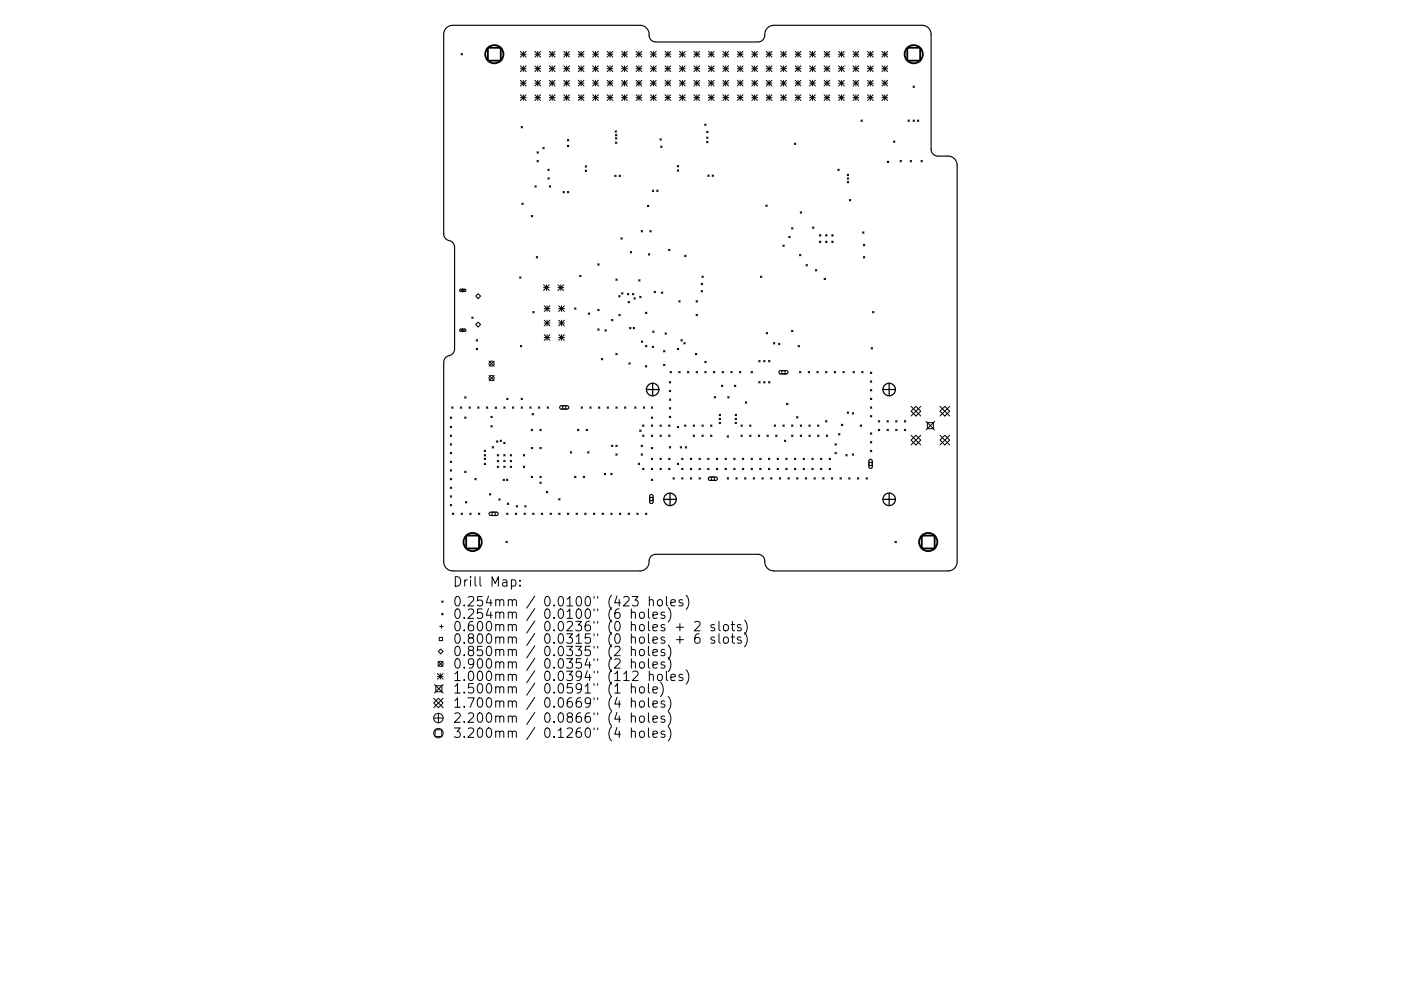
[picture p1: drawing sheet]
<svg xmlns="http://www.w3.org/2000/svg" width="297mm" height="210mm" viewBox="0 0 297 210" stroke-linecap="round" stroke-linejoin="round" font-family="sans-serif">
<defs><g id="words">
<g font-size="2.8">
<text x="96" y="124.5">Drill Map:</text>
<text x="96" y="128.7">0.254mm / 0.0100&quot; (423 holes)</text>
<text x="96" y="131.3">0.254mm / 0.0100&quot; (6 holes)</text>
<text x="96" y="133.9">0.600mm / 0.0236&quot; (0 holes + 2 slots)</text>
<text x="96" y="136.6">0.800mm / 0.0315&quot; (0 holes + 6 slots)</text>
<text x="96" y="139.2">0.850mm / 0.0335&quot; (2 holes)</text>
<text x="96" y="141.9">0.900mm / 0.0354&quot; (2 holes)</text>
<text x="96" y="144.5">1.000mm / 0.0394&quot; (112 holes)</text>
<text x="96" y="147.1">1.500mm / 0.0591&quot; (1 hole)</text>
<text x="96" y="150.1">1.700mm / 0.0669&quot; (4 holes)</text>
<text x="96" y="153.3">2.200mm / 0.0866&quot; (4 holes)</text>
<text x="96" y="156.5">3.200mm / 0.1260&quot; (4 holes)</text>
</g>
</g></defs>
<path d="M94.6 5.9l.7-.4 .7-.1h39.7a2.09 2.09 0 0 1 2 2.4l.4 .8 .8 .3h21.8a1.57 1.57 0 0 0 1.5-1.9 1.94 1.94 0 0 1 1.9-1.6h31.4a1.93 1.93 0 0 1 1.9 1.9v24.4a1.45 1.45 0 0 0 1.5 1.4h2.1a1.93 1.93 0 0 1 1.9 2v84.1a1.93 1.93 0 0 1-1.9 1.9h-36.9a2.09 2.09 0 0 1-2-2.4l-.5-.8-.8-.3h-21.7a1.57 1.57 0 0 0-1.5 1.9 1.94 1.94 0 0 1-1.9 1.6h-39.7a1.93 1.93 0 0 1-1.9-1.9v-42.3a1.73 1.73 0 0 1 1.6-1.6l.4-.5 .3-.7v-21.6a1.7 1.7 0 0 0-1.6-1.6l-.5-.5-.2-.8v-42.3l.1-.7zM97.5 61.4h1.1l.2 .3-.2 .1h-.9l-.2-.1zM97.5 69.9l1.1-.1 .2 .3-.2 .2h-.9l-.2-.2zM165.3 78.7l1.5-.1 .2 .2 .1 .2-.3 .3h-1.4l-.2-.2zM118.8 86.2l1.5-.1 .3 .4-.3 .3h-1.3l-.3-.2zM184.3 97.6l.4-.1 .2 .3v1.3l-.3 .3-.2-.1-.2-.2zM103.8 108.8l1.5-.1 .3 .4-.3 .3h-1.3l-.3-.3zM137.8 105l.4-.1 .3 .3v1.3l-.3 .3h-.3l-.2-.3zM150.3 101.3l1.5-.1 .2 .2 .1 .2-.3 .3h-1.3l-.3-.2z" fill="none" stroke="#000" stroke-width=".24"/>
<g fill="none" stroke="#000" stroke-width=".21">
<path d="M97.8 11.3l.3 .4M98.1 11.3l-.3 .4M110.3 10.9l1.2 1.2M110.3 11.5h1.2M110.3 14l1.2 1.2M110.3 14.6h1.2M110.3 17l1.2 1.3M110.3 17.6h1.2M110.9 10.9v1.2M110.9 14v1.2M110.9 17v1.3M111.5 10.9l-1.2 1.2"/>
<path d="M111.5 14l-1.2 1.2M111.5 17l-1.2 1.3M113.4 10.9l1.2 1.2M113.4 14l1.2 1.2M113.4 11.5h1.2M113.4 17l1.2 1.2M113.4 14.6h1.2M113.4 17.6h1.2M114 10.9v1.2M114 14v1.2M114 17v1.2M114.6 10.9l-1.2 1.2"/>
<path d="M114.6 14l-1.2 1.2M114.6 17l-1.2 1.2M116.5 14l1.2 1.2M116.5 17l1.2 1.2M116.5 11.5h1.2M116.5 14.6h1.2M116.5 17.6h1.2M116.5 10.9l1.2 1.2M117.1 10.9v1.2M117.1 14v1.2M117.1 17v1.2M117.7 14l-1.2 1.2"/>
<path d="M117.7 17l-1.2 1.2M117.7 10.9l-1.2 1.2M119.5 17l1.2 1.2M119.5 11.5h1.2M119.5 14.6h1.2M119.5 17.6h1.2M119.5 14l1.2 1.2M119.5 10.9l1.2 1.2M120.1 10.9v1.2M120.1 14v1.2M120.1 17v1.2M120.7 10.9l-1.2 1.2"/>
<path d="M120.7 14l-1.2 1.2M120.7 17l-1.2 1.2M122.6 11.5h1.2M122.6 14.6h1.2M122.6 17.6h1.2M122.6 17l1.2 1.2M122.6 14l1.2 1.2M122.6 10.9l1.2 1.2M123.2 10.9v1.2M123.2 14v1.2M123.2 17v1.2M123.8 10.9l-1.2 1.2"/>
<path d="M123.8 14l-1.2 1.2M123.8 17l-1.2 1.2M125.7 11.5h1.2M125.7 14.6h1.2M125.7 17.6h1.2M125.7 17l1.2 1.2M125.7 10.9l1.2 1.2M125.7 14l1.2 1.2M126.3 10.9v1.2M126.3 14v1.2M126.3 17v1.2M126.9 10.9l-1.2 1.2"/>
<path d="M126.9 14l-1.2 1.2M126.9 17l-1.2 1.2M128.7 11.5h1.2M128.7 14.6h1.2M128.7 17.6h1.2M128.7 14l1.2 1.2M128.7 17l1.2 1.2M128.7 10.9l1.2 1.2M129.3 10.9v1.2M129.3 14v1.2M129.3 17v1.2M129.9 10.9l-1.2 1.2"/>
<path d="M129.9 14l-1.2 1.2M129.9 17l-1.2 1.2M131.8 11.5h1.2M131.8 14.6h1.2M131.8 17.6h1.2M131.8 17l1.2 1.2M131.8 14l1.2 1.2M131.8 10.9l1.2 1.2M132.4 10.9v1.2M132.4 14v1.2M132.4 17v1.2M133 10.9l-1.2 1.2"/>
<path d="M133 14l-1.2 1.2M133 17l-1.2 1.2M134.9 11.5h1.2M134.9 14.6h1.2M134.9 17.6h1.2M134.9 17l1.2 1.2M134.9 14l1.2 1.2M134.9 10.9l1.2 1.2M135.5 10.9v1.2M135.5 14v1.2M135.5 17v1.2M136.1 17l-1.2 1.2"/>
<path d="M136.1 10.9l-1.2 1.2M136.1 14l-1.2 1.2M137.9 11.5h1.2M137.9 14.6h1.2M137.9 17.6h1.2M137.9 17l1.2 1.2M137.9 14l1.2 1.2M137.9 10.9l1.2 1.2M138.5 10.9v1.2M138.5 14v1.2M138.5 17v1.2M139.1 14l-1.2 1.2"/>
<path d="M139.1 17l-1.2 1.2M139.1 10.9l-1.2 1.2M141 11.5h1.2M141 14.6h1.2M141 17.6h1.2M141 17l1.2 1.2M141 14l1.2 1.2M141 10.9l1.2 1.2M141.6 10.9v1.2M141.6 14v1.2M141.6 17v1.2M142.2 10.9l-1.2 1.2"/>
<path d="M142.2 14l-1.2 1.2M142.2 17l-1.2 1.2M144.1 11.5h1.2M144.1 14.6h1.2M144.1 17.6h1.2M144.1 17l1.2 1.2M144.1 10.9l1.2 1.2M144.1 14l1.2 1.2M144.7 10.9v1.2M144.7 14v1.2M144.7 17v1.2M145.3 10.9l-1.2 1.2"/>
<path d="M145.3 14l-1.2 1.2M145.3 17l-1.2 1.2M147.1 11.5h1.2M147.1 14.6h1.2M147.1 17.6h1.2M147.1 17l1.2 1.2M147.1 10.9l1.2 1.2M147.1 14l1.2 1.2M147.7 10.9v1.2M147.7 14v1.2M147.7 17v1.2M148.3 10.9l-1.2 1.2"/>
<path d="M148.3 14l-1.2 1.2M148.3 17l-1.2 1.2M150.2 11.5h1.2M150.2 14.6h1.2M150.2 17.6h1.2M150.2 14l1.2 1.2M150.2 17l1.2 1.2M150.2 10.9l1.2 1.2M150.8 10.9v1.2M150.8 14v1.2M150.8 17v1.2M151.4 17l-1.2 1.2"/>
<path d="M151.4 10.9l-1.2 1.2M151.4 14l-1.2 1.2M153.3 11.5h1.2M153.3 14.6h1.2M153.3 17.6h1.2M153.3 17l1.2 1.2M153.3 14l1.2 1.2M153.3 10.9l1.2 1.2M153.9 10.9v1.2M153.9 14v1.2M153.9 17v1.2M154.5 10.9l-1.2 1.2"/>
<path d="M154.5 17l-1.2 1.2M154.5 14l-1.2 1.2M156.3 11.5h1.2M156.3 14.6h1.2M156.3 17.6h1.2M156.3 17l1.2 1.2M156.3 14l1.2 1.2M156.3 10.9l1.2 1.2M156.9 10.9v1.2M156.9 14v1.2M156.9 17v1.2M157.5 10.9l-1.2 1.2"/>
<path d="M157.5 14l-1.2 1.2M157.5 17l-1.2 1.2M159.4 11.5h1.2M159.4 14.6h1.2M159.4 17.6h1.2M159.4 17l1.2 1.2M159.4 14l1.2 1.2M159.4 10.9l1.2 1.2M160 10.9v1.2M160 14v1.2M160 17v1.2M160.6 10.9l-1.2 1.2"/>
<path d="M160.6 14l-1.2 1.2M160.6 17l-1.2 1.2M162.5 11.5h1.2M162.5 14.6h1.2M162.5 17.6h1.2M162.5 17l1.2 1.2M162.5 14l1.2 1.2M162.5 10.9l1.2 1.2M163.1 10.9v1.2M163.1 14v1.2M163.1 17v1.2M163.7 10.9l-1.2 1.2"/>
<path d="M163.7 14l-1.2 1.2M163.7 17l-1.2 1.2M165.5 11.5h1.2M165.5 14.6h1.2M165.5 17.6h1.2M165.5 17l1.2 1.2M165.5 10.9l1.2 1.2M165.5 14l1.2 1.2M166.1 10.9v1.2M166.1 14v1.2M166.1 17v1.2M166.7 10.9l-1.2 1.2"/>
<path d="M166.7 14l-1.2 1.2M166.7 17l-1.2 1.2M168.6 11.5h1.2M168.6 14.6h1.2M168.6 17.6h1.2M168.6 17l1.2 1.2M168.6 10.9l1.2 1.2M168.6 14l1.2 1.2M169.2 10.9v1.2M169.2 14v1.2M169.2 17v1.2M169.8 10.9l-1.2 1.2"/>
<path d="M169.8 14l-1.2 1.2M169.8 17l-1.2 1.2M171.7 11.5h1.2M171.7 14.6h1.2M171.7 17.6h1.2M171.7 14l1.2 1.2M171.7 17l1.2 1.2M171.7 10.9l1.2 1.2M172.3 10.9v1.2M172.3 14v1.2M172.3 17v1.2M172.9 10.9l-1.2 1.2"/>
<path d="M172.9 14l-1.2 1.2M172.9 17l-1.2 1.2M174.7 11.5h1.2M174.7 14.6h1.2M174.7 17.6h1.2M174.7 17l1.2 1.2M174.7 14l1.2 1.2M174.7 10.9l1.2 1.2M175.3 10.9v1.2M175.3 14v1.2M175.3 17v1.2M175.9 10.9l-1.2 1.2"/>
<path d="M175.9 14l-1.2 1.2M175.9 17l-1.2 1.2M177.8 11.5h1.2M177.8 14.6h1.2M177.8 17.6h1.2M177.8 17l1.2 1.2M177.8 14l1.2 1.2M177.8 10.9l1.2 1.2M178.4 10.9v1.2M178.4 14v1.2M178.4 17v1.2M179 10.9l-1.2 1.2"/>
<path d="M179 14l-1.2 1.2M179 17l-1.2 1.2M180.9 11.5h1.2M180.9 14.6h1.2M180.9 17.6h1.2M180.9 17l1.2 1.2M180.9 14l1.2 1.2M180.9 10.9l1.2 1.2M181.5 10.9v1.2M181.5 14v1.2M181.5 17v1.2M182.1 10.9l-1.2 1.2"/>
<path d="M182.1 14l-1.2 1.2M182.1 17l-1.2 1.2M183.9 11.5h1.2M183.9 14.6h1.2M183.9 17.6h1.2M183.9 17l1.2 1.2M183.9 14l1.2 1.2M183.9 10.9l1.2 1.2M184.5 10.9v1.2M184.5 14v1.2M184.5 17v1.2M185.1 17l-1.2 1.2"/>
<path d="M185.1 10.9l-1.2 1.2M185.1 14l-1.2 1.2M187 11.5h1.2M187 14.6h1.2M187 17.6h1.2M187 17l1.2 1.2M187 10.9l1.2 1.2M187 14l1.2 1.2M187.6 10.9v1.2M187.6 14v1.2M187.6 17v1.2M188.2 10.9l-1.2 1.2"/>
<path d="M188.2 14l-1.2 1.2M188.2 17l-1.2 1.2M193.6 18.2l.3 .4M193.9 18.2l-.3 .4M110.3 20.1l1.2 1.2M110.3 20.7h1.2M110.5 26.8l.3 .3M110.8 26.8l-.3 .3M110.9 20.1v1.2M111.5 20.1l-1.2 1.2M113.4 39.4l.3 .3M113.4 20.1l1.2 1.2"/>
<path d="M113.4 20.7h1.2M113.7 39.4l-.3 .3M113.9 32.2l.3 .3M113.9 34l.3 .3M114 20.1v1.2M114.2 32.2l-.3 .3M114.2 34l-.3 .3M114.6 20.1l-1.2 1.2M115.1 31.3l.3 .3M115.4 31.3l-.3 .3M116.2 35.9l.3 .3M116.2 37.7l.3 .3"/>
<path d="M116.5 35.9l-.3 .3M116.5 37.7l-.3 .3M116.5 39.4l.3 .3M116.5 20.1l1.2 1.2M116.5 20.7h1.2M116.8 39.4l-.3 .3M117.1 20.1v1.2M117.7 20.1l-1.2 1.2M119.5 20.1l1.2 1.2M119.5 20.7h1.2M120.1 20.1v1.2M120.3 29.6l.3 .3"/>
<path d="M120.3 30.8l.3 .3M120.6 29.6l-.3 .3M120.6 30.8l-.3 .3M120.7 20.1l-1.2 1.2M122.6 20.1l1.2 1.2M122.6 20.7h1.2M123.2 20.1v1.2M123.8 20.1l-1.2 1.2M124.1 35.2l.3 .3M124.1 36.1l.3 .3M124.4 35.2l-.3 .3M124.4 36.1l-.3 .3"/>
<path d="M125.7 20.7h1.2M125.7 20.1l1.2 1.2M126.3 20.1v1.2M126.9 20.1l-1.2 1.2M128.7 20.7h1.2M128.7 20.1l1.2 1.2M129.3 20.1v1.2M129.9 20.1l-1.2 1.2M130.3 37.2l.3 .3M130.4 27.8l.3 .3M130.5 28.5l.3 .3M130.5 29.2l.3 .3"/>
<path d="M130.5 30.1l.3 .3M130.6 37.2l-.3 .3M130.7 27.8l-.3 .3M130.8 28.5l-.3 .3M130.8 29.2l-.3 .3M130.8 30.1l-.3 .3M131.3 37.2l.3 .3M131.6 37.2l-.3 .3M131.8 20.7h1.2M131.8 20.1l1.2 1.2M132.4 20.1v1.2M133 20.1l-1.2 1.2"/>
<path d="M134.9 20.7h1.2M134.9 20.1l1.2 1.2M135.5 20.1v1.2M136.1 20.1l-1.2 1.2M137.9 20.7h1.2M137.9 20.1l1.2 1.2M138.5 20.1v1.2M139.1 20.1l-1.2 1.2M139.9 29.4l.3 .3M140.1 31l.3 .3M140.2 29.4l-.3 .3M140.4 31l-.3 .3"/>
<path d="M141 20.7h1.2M141 20.1l1.2 1.2M141.6 20.1v1.2M142.2 20.1l-1.2 1.2M143.6 35.1l.3 .3M143.6 36l.3 .3M143.9 35.1l-.3 .3M143.9 36l-.3 .3M144.1 20.7h1.2M144.1 20.1l1.2 1.2M144.7 20.1v1.2M145.3 20.1l-1.2 1.2"/>
<path d="M147.1 20.7h1.2M147.1 20.1l1.2 1.2M147.7 20.1v1.2M148.3 20.1l-1.2 1.2M149.4 26.3l.3 .3M149.7 26.3l-.3 .3M149.8 27.8l.3 .3M149.8 29.1l.3 .3M149.8 30l.3 .3M150.1 37.1l.3 .3M150.1 27.8l-.3 .3M150.1 29.1l-.3 .3"/>
<path d="M150.1 30l-.3 .3M150.2 20.7h1.2M150.2 20.1l1.2 1.2M150.4 37.1l-.3 .3M150.8 20.1v1.2M151 37.1l.3 .3M151.3 37.1l-.3 .3M151.4 20.1l-1.2 1.2M153.3 20.7h1.2M153.3 20.1l1.2 1.2M153.9 20.1v1.2M154.5 20.1l-1.2 1.2"/>
<path d="M156.3 20.7h1.2M156.3 20.1l1.2 1.2M156.9 20.1v1.2M157.5 20.1l-1.2 1.2M159.4 20.7h1.2M159.4 20.1l1.2 1.2M160 20.1v1.2M160.6 20.1l-1.2 1.2M162.5 20.7h1.2M162.5 20.1l1.2 1.2M163.1 20.1v1.2M163.7 20.1l-1.2 1.2"/>
<path d="M165.5 20.7h1.2M165.5 20.1l1.2 1.2M166.1 20.1v1.2M166.7 20.1l-1.2 1.2M168.4 30.4l.3 .3M168.6 20.7h1.2M168.6 20.1l1.2 1.2M168.7 30.4l-.3 .3M169.2 20.1v1.2M169.8 20.1l-1.2 1.2M171.7 20.7h1.2M171.7 20.1l1.2 1.2"/>
<path d="M172.3 20.1v1.2M172.9 20.1l-1.2 1.2M174.7 20.7h1.2M174.7 20.1l1.2 1.2M175.3 20.1v1.2M175.9 20.1l-1.2 1.2M177.6 35.9l.3 .3M177.8 20.7h1.2M177.8 20.1l1.2 1.2M177.9 35.9l-.3 .3M178.4 20.1v1.2M179 20.1l-1.2 1.2"/>
<path d="M179.6 37l.3 .3M179.6 37.7l.3 .3M179.6 38.5l.3 .3M179.9 38.5l-.3 .3M179.9 37.7l-.3 .3M179.9 37l-.3 .3M180.9 20.7h1.2M180.9 20.1l1.2 1.2M181.5 20.1v1.2M182.1 20.1l-1.2 1.2M182.5 25.5l.3 .3M182.8 25.5l-.3 .3"/>
<path d="M183.9 20.7h1.2M183.9 20.1l1.2 1.2M184.5 20.1v1.2M185.1 20.1l-1.2 1.2M187 20.7h1.2M187 20.1l1.2 1.2M187.6 20.1v1.2M188.1 34.2l.3 .3M188.2 20.1l-1.2 1.2M188.4 34.2l-.3 .3M189.4 29.9l.3 .3M189.7 29.9l-.3 .3"/>
<path d="M190.8 34l.3 .3M191.1 34l-.3 .3M192.5 25.5l.3 .3M192.8 25.5l-.3 .3M193 34l.3 .3M193.3 34l-.3 .3M193.6 25.5l.3 .3M193.9 25.5l-.3 .3M194.5 25.5l.3 .3M194.8 25.5l-.3 .3M195.3 34l.3 .3M195.6 34l-.3 .3"/>
<path d="M110.2 58.7l.3 .3M110.5 58.7l-.3 .3M110.6 43.1l.3 .3M110.9 43.1l-.3 .3M112.6 45.7l.3 .3M112.9 45.7l-.3 .3M113.7 54.4l.3 .3M114 54.4l-.3 .3M119.4 40.6l.3 .3M119.7 40.6l-.3 .3M120.3 40.6l.3 .3M120.6 40.6l-.3 .3"/>
<path d="M122.9 58.4l.3 .3M123.2 58.4l-.3 .3M126.7 56l.3 .3M127 56l-.3 .3M130.6 59.2l.3 .3M130.9 59.2l-.3 .3M131.6 50.4l.3 .4M131.9 50.4l-.3 .4M133.6 53.4l.3 .3M133.9 53.4l-.3 .3M135.4 59.3l.3 .3M135.7 59.3l-.3 .3"/>
<path d="M135.9 48.9l.3 .3M136.2 48.9l-.3 .3M137.3 43.5l.3 .3M137.5 53.8l.3 .3M137.6 43.5l-.3 .3M137.8 53.8l-.3 .3M137.8 48.9l.3 .3M138.1 48.9l-.3 .3M138.3 40.3l.3 .3M138.6 40.3l-.3 .3M139.2 40.3l.3 .3M139.5 40.3l-.3 .3"/>
<path d="M141.8 52.9l.3 .3M142.1 52.9l-.3 .3M145.2 54.2l.3 .3M145.5 54.2l-.3 .3M148.8 58.6l.3 .3M149.1 58.6l-.3 .3M161.2 58.6l.3 .3M161.5 58.6l-.3 .3M162.4 43.5l.3 .3M162.7 43.5l-.3 .3M166 52l.3 .3M166.3 52l-.3 .3"/>
<path d="M167.2 50.1l.3 .3M167.5 50.1l-.3 .3M167.8 48.3l.3 .3M168.1 48.3l-.3 .3M169.5 54l.3 .3M169.7 44.9l.3 .3M169.8 54l-.3 .3M170 44.9l-.3 .3M170.9 56.1l.3 .3M171.2 56.1l-.3 .3M172.3 48.1l.3 .4M172.6 48.1l-.3 .4"/>
<path d="M172.9 57.2l.3 .3M173.2 57.2l-.3 .3M174.7 59l.3 .3M175 59l-.3 .3M180.1 42.3l.3 .3M180.4 42.3l-.3 .3M182.9 49.2l.3 .3M183 51.9l.4 .3M183 54.4l.4 .3M183.2 49.2l-.3 .3M183.4 51.9l-.4 .3M183.4 54.4l-.4 .3"/>
<path d="M97.8 61.6h.7M97.8 70.1h.7M98.1 61.2v.8M98.1 69.7v.7M100 67.3l.3 .3M100.3 67.3l-.3 .3M100.9 68.9l.5-.6 .5 .6-.5 .5zM101 72.1l.3 .3M101 73.9l.3 .3M101.3 72.1l-.3 .3M101.3 73.9l-.3 .3M101.4 62.3l.5 .5-.5 .5-.5-.5z"/>
<path d="M103.7 76.6l1.1 1.1M103.7 79.7l1.1 1.1M104.8 76.6l-1.1 1.1M104.8 79.7l-1.1 1.1M110.3 73.3l.3 .3M110.6 73.3l-.3 .3M113 66.1l.3 .3M113.3 66.1l-.3 .3M115.2 60.4l1.2 1.2M115.2 61h1.2M115.4 64.9l1.2 1.2M115.4 65.5h1.2"/>
<path d="M115.4 67.9l1.2 1.2M115.4 68.5h1.2M115.4 71l1.2 1.2M115.4 71.6h1.2M115.8 60.4v1.2M116 64.9v1.2M116 67.9v1.2M116 71v1.2M116.4 60.4l-1.2 1.2M116.6 64.9l-1.2 1.2M116.6 67.9l-1.2 1.2M116.6 71l-1.2 1.2"/>
<path d="M118.3 60.4l1.2 1.2M118.3 61h1.2M118.5 64.9l1.2 1.2M118.5 67.9l1.2 1.2M118.5 65.5h1.2M118.5 71l1.2 1.2M118.5 68.5h1.2M118.5 71.6h1.2M118.9 60.4v1.2M119.1 64.9v1.2M119.1 67.9v1.2M119.1 71v1.2"/>
<path d="M119.5 60.4l-1.2 1.2M119.7 64.9l-1.2 1.2M119.7 67.9l-1.2 1.2M119.7 71l-1.2 1.2M121.8 65.3l.3 .3M122.1 65.3l-.3 .3M124.7 66.4l.3 .3M125 66.4l-.3 .3M126.7 65.6l.3 .3M126.7 69.8l.3 .3M127 65.6l-.3 .3M127 69.8l-.3 .3"/>
<path d="M127.5 76l.3 .4M127.8 76l-.3 .4M128.3 70l.3 .3M128.6 70l-.3 .3M129.6 67.8l.3 .3M129.9 67.8l-.3 .3M130.6 75l.3 .3M130.9 75l-.3 .3M131.2 62.7l.3 .3M131.2 66.7l.3 .3M131.5 62.7l-.3 .3M131.5 66.7l-.3 .3"/>
<path d="M131.8 62.1l.3 .3M132.1 62.1l-.3 .3M133 62.3l.3 .3M133.2 63.9l.3 .3M133.3 62.3l-.3 .3M133.3 77l.3 .3M133.5 63.9l-.3 .3M133.5 69.5l.3 .3M133.6 77l-.3 .3M133.8 69.5l-.3 .3M134.1 62.3l.3 .3M134.2 69.5l.3 .3"/>
<path d="M134.4 62.3l-.3 .3M134.4 63.2l.3 .3M134.5 69.5l-.3 .3M134.7 63.2l-.3 .3M135.6 62.9l.3 .3M135.9 62.9l-.3 .3M136 72.3l.3 .3M136.3 72.3l-.3 .3M136.8 77.6l.3 .3M136.8 66.2l.4 .3M136.8 73.3l.4 .3M137.1 77.6l-.3 .3"/>
<path d="M137.2 66.2l-.4 .3M137.2 73.3l-.4 .3M138.3 73.4l.3 .3M138.4 70.2l.3 .3M138.6 73.4l-.3 .3M138.7 70.2l-.3 .3M138.7 61.8l.3 .3M139 61.8l-.3 .3M140.2 61.9l.3 .4M140.5 61.9l-.3 .4M140.7 74.4l.3 .3M140.7 77.3l.3 .3"/>
<path d="M141 74.4l-.3 .3M141 77.3l-.3 .3M141 70.6l.3 .3M141.3 70.6l-.3 .3M142.1 78.8l.3 .3M142.4 78.8l-.3 .3M143.6 73.9l.3 .3M143.9 73.9l-.3 .3M143.9 63.8l.3 .3M143.9 78.8l.3 .3M144.2 78.8l-.3 .3M144.2 63.8l-.3 .3"/>
<path d="M144.4 72.1l.3 .3M144.7 72.1l-.3 .3M145 72.7l.3 .3M145.3 72.7l-.3 .3M145.7 78.8l.3 .3M146 78.8l-.3 .3M147.4 75l.3 .3M147.6 63.8l.3 .3M147.6 66.7l.3 .3M147.6 78.8l.3 .3M147.7 75l-.3 .3M147.9 66.7l-.3 .3"/>
<path d="M147.9 63.8l-.3 .3M147.9 78.8l-.3 .3M148.7 61.6l.3 .3M148.7 60.1l.3 .3M149 61.6l-.3 .3M149 60.1l-.3 .3M149.4 78.8l.3 .3M149.4 76.7l.3 .3M149.7 78.8l-.3 .3M149.7 76.7l-.3 .3M151.3 78.8l.3 .3M151.6 78.8l-.3 .3"/>
<path d="M153.1 78.8l.3 .3M153.4 78.8l-.3 .3M154.9 78.8l.3 .3M155.2 78.8l-.3 .3M156.8 78.8l.3 .3M157.1 78.8l-.3 .3M159.2 78.8l.3 .3M159.5 78.8l-.3 .3M160.9 76.5l.3 .3M161.2 76.5l-.3 .3M161.9 76.5l.3 .3M162.2 76.5l-.3 .3"/>
<path d="M162.5 70.5l.3 .3M162.8 70.5l-.3 .3M162.9 76.5l.4 .3M163.3 76.5l-.4 .3M164 72.7l.3 .3M164.3 72.7l-.3 .3M165.1 72.8l.3 .3M165.4 72.8l-.3 .3M165.8 78.6h.7v.7h-.7zM167.8 70.1l.3 .3M168.1 70.1l-.3 .3M169.2 73.3l.3 .3"/>
<path d="M169.5 73.3l-.3 .3M169.5 78.8l.3 .3M169.8 78.8l-.3 .3M171.3 78.8l.4 .3M171.7 78.8l-.4 .3M173.2 78.8l.3 .3M173.5 78.8l-.3 .3M175 78.8l.3 .3M175.3 78.8l-.3 .3M176.9 78.8l.3 .3M177.2 78.8l-.3 .3M178.7 78.8l.3 .3"/>
<path d="M179 78.8l-.3 .3M180.9 78.8l.3 .3M181.2 78.8l-.3 .3M182.7 78.8l.3 .3M183 78.8l-.3 .3M184.5 79l.3 .3M184.7 73.7l.3 .4M184.8 79l-.3 .3M185 66.1l.3 .3M185 73.7l-.3 .4M185.3 66.1l-.3 .3M95.5 88.5l.3 .3"/>
<path d="M95.5 90.5l.3 .3M95.5 92.3l.3 .3M95.5 94.1l.3 .3M95.5 96l.3 .3M95.5 97.8l.3 .3M95.5 99.7l.3 .3M95.8 88.5l-.3 .3M95.8 90.5l-.3 .3M95.8 92.3l-.3 .3M95.8 94.1l-.3 .3M95.8 96l-.3 .3M95.8 97.8l-.3 .3"/>
<path d="M95.8 99.7l-.3 .3M95.8 86.3l.3 .3M96.1 86.3l-.3 .3M97.6 86.3l.3 .3M97.9 86.3l-.3 .3M98.5 100l.3 .3M98.5 84.2l.3 .3M98.5 88.5l.3 .3M98.8 100l-.3 .3M98.8 84.2l-.3 .3M98.8 88.5l-.3 .3M99.4 86.3l.3 .3"/>
<path d="M99.7 86.3l-.3 .3M101.3 86.3l.3 .3M101.6 86.3l-.3 .3M102.7 95.5l.3 .3M102.7 96.4l.3 .3M102.7 98.3l.3 .3M102.7 97.2l.3 .3M103 95.5l-.3 .3M103 96.4l-.3 .3M103 98.3l-.3 .3M103 97.2l-.3 .3M103.1 86.3l.3 .3"/>
<path d="M103.4 86.3l-.3 .3M104.1 88.3l.3 .3M104.1 90.3l.3 .3M104.3 94.8l.4 .3M104.4 88.3l-.3 .3M104.4 90.3l-.3 .3M104.7 94.8l-.4 .3M105 86.4l.3 .3M105.3 93.5l.3 .3M105.3 86.4l-.3 .3M105.4 96.4l.3 .3M105.4 97.7l.3 .3"/>
<path d="M105.4 98.9l.3 .3M105.6 93.5l-.3 .3M105.7 96.4l-.3 .3M105.7 97.7l-.3 .3M105.7 98.9l-.3 .3M106 93.4l.3 .3M106.3 93.4l-.3 .3M106.8 93.8l.3 .3M106.8 96.4l.3 .3M106.8 97.7l.3 .3M106.8 86.3l.3 .3M106.8 98.9l.3 .3"/>
<path d="M107.1 93.8l-.3 .3M107.1 96.4l-.3 .3M107.1 97.7l-.3 .3M107.1 86.3l-.3 .3M107.1 98.9l-.3 .3M107.4 84.5l.3 .3M107.7 84.5l-.3 .3M108.2 96.4l.3 .3M108.2 97.7l.3 .3M108.2 98.9l.3 .3M108.5 96.4l-.3 .3M108.5 97.7l-.3 .3"/>
<path d="M108.5 98.9l-.3 .3M108.6 86.3l.3 .3M108.9 86.3l-.3 .3M110.5 84.5l.3 .3M110.5 86.3l.3 .3M110.8 84.5l-.3 .3M110.8 86.3l-.3 .3M110.9 96.4l.3 .3M110.9 98.9l.3 .3M111.2 96.4l-.3 .3M111.2 98.9l-.3 .3M112.3 86.3l.3 .3"/>
<path d="M112.6 91.1l.3 .3M112.6 94.9l.3 .3M112.6 86.3l-.3 .3M112.8 87.7l.3 .3M112.9 91.1l-.3 .3M112.9 94.9l-.3 .3M113.1 87.7l-.3 .3M114.2 86.3l.3 .3M114.5 91.1l.3 .3M114.5 94.9l.3 .3M114.5 86.3l-.3 .3M114.8 91.1l-.3 .3"/>
<path d="M114.8 94.9l-.3 .3M116 86.3l.3 .3M116.3 86.3l-.3 .3M119.3 86.1h.7v.7h-.7zM120.9 95.8l.3 .3M121.2 95.8l-.3 .3M122.4 91.1l.3 .3M122.7 91.1l-.3 .3M123.2 86.3l.3 .3M123.5 86.3l-.3 .3M124.3 91.1l.3 .3M124.6 91.1l-.3 .3"/>
<path d="M124.6 95.8l.3 .3M124.9 95.8l-.3 .3M125 86.3l.3 .3M125.3 86.3l-.3 .3M126.9 86.3l.3 .3M127.2 86.3l-.3 .3M128.7 86.3l.3 .3M129 86.3l-.3 .3M129.6 94.4l.3 .4M129.9 94.4l-.3 .4M130.6 86.3l.3 .3M130.6 94.4l.3 .4"/>
<path d="M130.6 96.3l.3 .3M130.9 86.3l-.3 .3M130.9 94.4l-.3 .4M130.9 96.3l-.3 .3M132.4 86.3l.3 .3M132.7 86.3l-.3 .3M134.5 86.3l.4 .3M134.9 86.3l-.4 .3M135.3 98.3l.3 .3M135.6 98.3l-.3 .3M135.6 91.2l.3 .3M135.9 91.2l-.3 .3"/>
<path d="M135.9 94.4l.3 .4M135.9 96.3l.3 .3M136.2 99.4l.3 .3M136.2 90.2l.3 .3M136.2 94.4l-.3 .4M136.2 96.3l-.3 .3M136.2 92.3l.3 .3M136.4 86.3l.3 .3M136.5 92.3l-.3 .3M136.5 90.2l-.3 .3M136.5 99.4l-.3 .3M136.7 86.3l-.3 .3"/>
<path d="M138.1 86.3l.3 .3M138.1 88.5l.3 .3M138.1 90.2l.3 .3M138.1 92.3l.3 .3M138.1 94.9l.3 .3M138.1 97.2l.3 .3M138.1 99.4l.3 .3M138.4 92.3l-.3 .3M138.4 86.3l-.3 .3M138.4 88.5l-.3 .3M138.4 90.2l-.3 .3M138.4 94.9l-.3 .3"/>
<path d="M138.4 97.2l-.3 .3M138.4 99.4l-.3 .3M139.9 99.4l.3 .3M139.9 90.2l.3 .3M139.9 92.3l.3 .3M139.9 97.2l.3 .3M140.2 92.3l-.3 .3M140.2 90.2l-.3 .3M140.2 97.2l-.3 .3M140.2 99.4l-.3 .3M141.8 90.2l.3 .3M141.8 92.3l.3 .3"/>
<path d="M141.8 97.2l.3 .3M141.8 99.4l.3 .3M141.9 81l.3 .3M141.9 82.8l.3 .3M141.9 84.6l.3 .3M141.9 86.5l.3 .3M141.9 88.3l.3 .3M141.9 94.8l.3 .3M142.1 90.2l-.3 .3M142.1 92.3l-.3 .3M142.1 97.2l-.3 .3M142.1 99.4l-.3 .3"/>
<path d="M142.2 81l-.3 .3M142.2 82.8l-.3 .3M142.2 84.6l-.3 .3M142.2 86.5l-.3 .3M142.2 88.3l-.3 .3M142.2 94.8l-.3 .3M143.6 90.5l.3 .3M143.6 98.3l.3 .3M143.9 90.5l-.3 .3M143.9 98.3l-.3 .3M144.2 94.8l.3 .3M144.5 94.8l-.3 .3"/>
<path d="M144.5 97.2l.3 .3M144.5 99.4l.3 .3M144.8 97.2l-.3 .3M144.8 99.4l-.3 .3M145.1 90.2l.3 .3M145.3 94.8l.3 .3M145.4 90.2l-.3 .3M145.6 94.8l-.3 .3M146.4 99.4l.3 .3M146.4 97.2l.3 .3M146.7 99.4l-.3 .3M146.7 97.2l-.3 .3"/>
<path d="M147 90.2l.3 .3M147 92.3l.3 .3M147.3 90.2l-.3 .3M147.3 92.3l-.3 .3M148.2 97.2l.3 .3M148.2 99.4l.3 .3M148.5 97.2l-.3 .3M148.5 99.4l-.3 .3M148.8 90.2l.3 .3M148.8 92.3l.3 .3M149.1 90.2l-.3 .3M149.1 92.3l-.3 .3"/>
<path d="M150 97.2l.3 .3M150 99.4l.3 .3M150.3 97.2l-.3 .3M150.3 99.4l-.3 .3M150.6 92.3l.4 .3M150.6 90.2l.4 .3M151 90.2l-.4 .3M151 92.3l-.4 .3M151.4 84.1l.3 .3M151.7 84.1l-.3 .3M151.9 97.2l.3 .3M151.9 99.4l.3 .3"/>
<path d="M152.2 97.2l-.3 .3M152.2 99.4l-.3 .3M152.5 87.9l.3 .3M152.5 88.7l.3 .3M152.5 89.6l.3 .3M152.8 89.6l-.3 .3M152.8 87.9l-.3 .3M152.8 88.7l-.3 .3M152.9 81.7l.4 .3M153.3 81.7l-.4 .3M153.7 97.2l.3 .3M153.7 99.4l.3 .3"/>
<path d="M154 97.2l-.3 .3M154 99.4l-.3 .3M154.2 92.5l.3 .3M154.3 84.1l.3 .3M154.5 92.5l-.3 .3M154.6 84.1l-.3 .3M155.6 97.2l.3 .3M155.6 99.4l.3 .3M155.7 81.7l.3 .3M155.9 89.6l.3 .3M155.9 97.2l-.3 .3M155.9 99.4l-.3 .3"/>
<path d="M155.9 87.9l.3 .3M155.9 88.7l.3 .3M156 81.7l-.3 .3M156.2 89.6l-.3 .3M156.2 87.9l-.3 .3M156.2 88.7l-.3 .3M157.1 92.3l.3 .3M157.1 90.2l.3 .3M157.4 90.2l-.3 .3M157.4 92.3l-.3 .3M157.4 97.2l.3 .3M157.4 99.4l.3 .3"/>
<path d="M157.7 97.2l-.3 .3M157.7 99.4l-.3 .3M158 85.2l.3 .4M158.3 85.2l-.3 .4M158.9 90.2l.3 .3M158.9 92.3l.3 .3M159.2 90.2l-.3 .3M159.2 92.3l-.3 .3M159.2 97.2l.3 .3M159.2 99.4l.3 .3M159.5 97.2l-.3 .3M159.5 99.4l-.3 .3"/>
<path d="M160.8 92.3l.3 .3M160.9 81l.3 .3M161.1 92.3l-.3 .3M161.1 97.2l.3 .3M161.1 99.4l.3 .3M161.2 81l-.3 .3M161.4 97.2l-.3 .3M161.4 99.4l-.3 .3M161.9 81l.3 .3M162.2 81l-.3 .3M162.6 92.3l.3 .3M162.9 92.3l-.3 .3"/>
<path d="M162.9 97.2l.3 .3M162.9 99.4l.3 .3M162.9 81l.4 .3M163.2 97.2l-.3 .3M163.2 99.4l-.3 .3M163.3 81l-.4 .3M164.1 90.2l.3 .3M164.4 90.2l-.3 .3M164.4 92.3l.4 .3M164.8 92.3l-.4 .3M164.8 97.2l.3 .3M164.8 99.4l.3 .3"/>
<path d="M165.1 97.2l-.3 .3M165.1 99.4l-.3 .3M166 90.2l.3 .3M166.3 90.2l-.3 .3M166.3 93.4l.3 .3M166.6 93.4l-.3 .3M166.6 97.2l.3 .3M166.6 99.4l.3 .3M166.7 85.6l.4 .3M166.9 97.2l-.3 .3M166.9 99.4l-.3 .3M167.1 85.6l-.4 .3"/>
<path d="M167.8 90.2l.3 .3M167.8 92.3l.3 .3M168.1 92.3l-.3 .3M168.1 90.2l-.3 .3M168.4 97.2l.3 .3M168.4 99.4l.3 .3M168.7 97.2l-.3 .3M168.7 99.4l-.3 .3M168.9 88.4l.3 .3M169.2 88.4l-.3 .3M169.7 90.2l.3 .3M169.7 92.3l.3 .3"/>
<path d="M170 92.3l-.3 .3M170 90.2l-.3 .3M170.3 99.4l.3 .3M170.3 97.2l.3 .3M170.6 97.2l-.3 .3M170.6 99.4l-.3 .3M171.5 90.2l.3 .3M171.5 92.3l.3 .3M171.8 90.2l-.3 .3M171.8 92.3l-.3 .3M172.1 99.4l.3 .3M172.1 97.2l.3 .3"/>
<path d="M172.4 97.2l-.3 .3M172.4 99.4l-.3 .3M173.3 90.2l.3 .3M173.3 92.3l.3 .3M173.6 92.3l-.3 .3M173.6 90.2l-.3 .3M174 97.2l.3 .3M174 99.4l.3 .3M174.3 97.2l-.3 .3M174.3 99.4l-.3 .3M175 89.2l.3 .3M175.2 92.3l.3 .3"/>
<path d="M175.3 89.2l-.3 .3M175.5 92.3l-.3 .3M175.8 97.2l.3 .3M175.8 99.4l.3 .3M176.1 97.2l-.3 .3M176.1 99.4l-.3 .3M177 96l.3 .3M177 94.1l.3 .3M177.3 94.1l-.3 .3M177.3 96l-.3 .3M177.8 92l.3 .3M178.1 92l-.3 .3"/>
<path d="M178.4 90l.3 .3M178.7 90l-.3 .3M179.3 96.4l.3 .3M179.6 96.4l-.3 .3M179.6 87.4l.3 .3M179.9 87.4l-.3 .3M180.7 96.3l.3 .3M180.7 87.5l.3 .4M181 87.5l-.3 .4M181 96.3l-.3 .3M182.4 90.2l.3 .3M182.7 90.2l-.3 .3"/>
<path d="M184.2 98.1h.7v.7h-.7zM184.5 93.7l.3 .3M184.5 95.5l.3 .3M184.5 80.8l.3 .3M184.5 82.6l.3 .3M184.5 84.5l.3 .3M184.5 86.3l.3 .3M184.5 88.2l.3 .3M184.5 91.8l.3 .3M184.8 80.8l-.3 .3M184.8 82.6l-.3 .3M184.8 84.5l-.3 .3"/>
<path d="M184.8 86.3l-.3 .3M184.8 88.2l-.3 .3M184.8 91.8l-.3 .3M184.8 93.7l-.3 .3M184.8 95.5l-.3 .3M186.2 89.2l.3 .3M186.2 91.1l.3 .3M186.5 89.2l-.3 .3M186.5 91.1l-.3 .3M188.1 91.1l.3 .3M188.1 89.2l.3 .3M188.4 89.2l-.3 .3"/>
<path d="M188.4 91.1l-.3 .3M189.9 91.1l.3 .3M189.9 89.2l.3 .3M190.2 89.2l-.3 .3M190.2 91.1l-.3 .3M191.7 91.1l.3 .3M191.7 89.2l.3 .3M192 89.2l-.3 .3M192 91.1l-.3 .3M193.2 86.2l2 2.1M193.2 92.3l2 2.1M194.2 86.2l1 1-1 1.1-1-1.1z"/>
<path d="M194.2 92.3l1 1.1-1 1-1-1zM195.2 92.3l-2 2.1M195.2 86.2l-2 2.1M196.4 89.4l1.8 1.8M196.6 89.7h1.3v1.2h-1.3zM198.2 89.4l-1.8 1.8M199.3 87.2l1-1 1 1-1 1.1zM199.3 93.4l1-1.1 1 1.1-1 1zM199.3 86.2l2 2.1M199.3 92.3l2 2.1M201.3 86.2l-2 2.1M201.3 92.3l-2 2.1"/>
<path d="M95.5 101.5l.3 .3M95.5 103.3l.3 .3M95.5 105.2l.3 .3M95.5 107l.3 .3M95.8 101.5l-.3 .3M95.8 103.3l-.3 .3M95.8 105.2l-.3 .3M95.8 107l-.3 .3M95.9 108.9l.3 .3M96.2 108.9l-.3 .3M97.8 108.9l.3 .3M98.1 108.9l-.3 .3"/>
<path d="M98.7 106.4l.3 .3M99 106.4l-.3 .3M99.6 108.9l.3 .3M99.9 108.9l-.3 .3M100.7 101.5l.3 .3M101 101.5l-.3 .3M101.4 108.9l.3 .3M101.7 108.9l-.3 .3M103.8 104.7l.3 .3M104.1 104.7l-.3 .3M104.3 108.7h.7v.7h-.7zM105.8 105.8l.3 .3"/>
<path d="M106.1 105.8l-.3 .3M106.7 101.7l.3 .3M107 101.7l-.3 .3M107.3 114.8l.3 .3M107.4 101.7l.3 .3M107.4 108.9l.3 .3M107.6 106.7l.3 .3M107.6 114.8l-.3 .3M107.7 101.7l-.3 .3M107.7 108.9l-.3 .3M107.9 106.7l-.3 .3M109.3 108.9l.3 .3"/>
<path d="M109.4 107.3l.3 .3M109.6 108.9l-.3 .3M109.7 107.3l-.3 .3M111.1 108.9l.3 .3M111.2 107.3l.3 .3M111.4 108.9l-.3 .3M111.5 107.3l-.3 .3M112.6 101l.3 .3M112.9 101l-.3 .3M112.9 108.9l.3 .3M113.2 108.9l-.3 .3M114.5 101l.3 .3"/>
<path d="M114.5 102.3l.3 .3M114.8 102.3l-.3 .3M114.8 101l-.3 .3M114.8 108.9l.3 .3M115.1 108.9l-.3 .3M115.8 104.3l.3 .3M116.1 104.3l-.3 .3M116.6 108.9l.3 .3M116.9 108.9l-.3 .3M118.4 105.8l.3 .3M118.5 108.9l.3 .3M118.7 105.8l-.3 .3"/>
<path d="M118.8 108.9l-.3 .3M120.3 108.9l.3 .3M120.6 108.9l-.3 .3M121.8 101l.3 .3M122.1 101l-.3 .3M122.1 108.9l.3 .3M122.4 108.9l-.3 .3M123.7 101l.3 .3M124 101l-.3 .3M124 108.9l.3 .3M124.3 108.9l-.3 .3M125.8 108.9l.3 .3"/>
<path d="M126.1 108.9l-.3 .3M127.6 108.9l.4 .3M128 108.9l-.4 .3M128.1 100.4l.3 .3M128.4 100.4l-.3 .3M129.5 100.4l.3 .3M129.5 108.9l.3 .3M129.8 100.4l-.3 .3M129.8 108.9l-.3 .3M131.3 108.9l.3 .3M131.6 108.9l-.3 .3M133.2 108.9l.3 .3"/>
<path d="M133.5 108.9l-.3 .3M135 108.9l.3 .3M135.3 108.9l-.3 .3M136.8 108.9l.4 .3M137.2 108.9l-.4 .3M137.8 105.5h.6v.7h-.6zM138.1 101.7l.3 .3M138.4 101.7l-.3 .3M142.7 101.3l.3 .4M143 101.3l-.3 .4M144.5 101.3l.3 .4M144.8 101.3l-.3 .4"/>
<path d="M146.4 101.3l.3 .4M146.7 101.3l-.3 .4M148.2 101.3l.3 .4M148.5 101.3l-.3 .4M150.8 101.2h.7v.7h-.7zM154.2 101.3l.3 .4M154.5 101.3l-.3 .4M156 101.3l.3 .4M156.3 101.3l-.3 .4M157.9 101.3l.3 .4M158.2 101.3l-.3 .4M159.7 101.3l.3 .4"/>
<path d="M160 101.3l-.3 .4M161.5 101.3l.3 .4M161.8 101.3l-.3 .4M163.4 101.3l.3 .4M163.7 101.3l-.3 .4M165.2 101.3l.3 .4M165.5 101.3l-.3 .4M167.1 101.3l.3 .4M167.4 101.3l-.3 .4M168.9 101.3l.3 .4M169.2 101.3l-.3 .4M170.7 101.3l.3 .4"/>
<path d="M171 101.3l-.3 .4M172.6 101.3l.3 .4M172.9 101.3l-.3 .4M174.4 101.3l.3 .4M174.7 101.3l-.3 .4M176.3 101.3l.3 .4M176.6 101.3l-.3 .4M178.1 101.3l.3 .4M178.4 101.3l-.3 .4M179.9 101.3l.3 .4M180.2 101.3l-.3 .4M181.8 101.3l.3 .4"/>
<path d="M182.1 101.3l-.3 .4M183.6 101.3l.3 .4M183.9 101.3l-.3 .4M189.7 114.8l.4 .3M190.1 114.8l-.4 .3M92.9 138.2l.5-.5 .6 .5-.6 .5zM93.1 135.2h.7v.7h-.7zM93.2 132.9h.8M93.6 132.6v.7M93.6 127.5l.4 .3M94 127.5l-.4 .3M108.4 123.1l.6-.1 .4 .4v.6l-.2 .3h-.8"/>
<path d="M110.2 124.2v.2M110.2 123.1v.2M133.9 130.1a.5 .5 0 0 1 .8 0v1.1M133.9 138a.5 .5 0 0 1 .8 .1v1M133.9 129.2v2M133.9 137.1v2M133.9 139.8v2M134.1 126.6h1.2l-.7 .7a.54 .54 0 0 1 .7 .4v.5l-.2 .3-.8 .1-.2-.2M135.7 130.1a.54 .54 0 0 1 .5-.2 .54 .54 0 0 1 .4 .3v.6a.54 .54 0 0 1-.5 .4 .54 .54 0 0 1-.5-.4zM135.7 138a.54 .54 0 0 1 .5-.2 .54 .54 0 0 1 .4 .4v.5a.54 .54 0 0 1-.5 .4 .54 .54 0 0 1-.5-.4zM137.5 129.2v1.7l.3 .3M137.5 137.1v1.7l.3 .3"/>
<path d="M137.5 139.8v1.7l.3 .3M137.7 127.4l.3-.2 .4 .1 .1 1.3M137.7 126.6v2M138.4 130.5l1-.2-.1-.3-.6-.1-.3 .2 .1 1h.8M138.4 138.5l1-.2-.1-.4-.6-.1-.3 .3 .1 .9h.8M139.5 127.4l.3-.2a.54 .54 0 0 1 .6 .4l-.1 .8-.5 .2-.4-.4zM140.9 130l-.5-.1-.3 .2 .1 .3 .7 .2v.5h-.8M140.9 137.9l-.5-.1-.3 .3 .1 .3 .7 .1v.5h-.8M141.3 126.6v1.7l.3 .3M141.7 128.9a2.29 2.29 0 0 1 0 3.1M141.7 136.8a2.29 2.29 0 0 1 0 3.1M141.7 139.5a2.29 2.29 0 0 1 0 3"/>
<path d="M142.2 127.9l1-.2-.1-.4-.6-.1-.3 .3 .1 1h.8M143.4 133.1h1.5M143.4 135.7h1.5M144.1 132.3v1.5M144.1 135v1.5M144.7 127.3l-.5-.1-.2 .3 .1 .3 .6 .2v.5h-.7M145.5 126.3a2.29 2.29 0 0 1 0 3M147.3 132l.3-.2 .6 .1a.54 .54 0 0 1 .1 .8l-1.1 1.1h1.2M148.2 134.5a.79 .79 0 0 0-.9 .8v.8l.2 .3 .6 .1 .2-.2 .1-.7-.2-.3-.5-.1-.4 .4M151.5 132.6l-.5-.1-.3 .3 .1 .3 .7 .2v.4h-.8M151.5 135.2l-.5-.1-.3 .3 .1 .3 .7 .2v.5h-.8M152.4 131.8v1.8l.3 .2"/>
<path d="M152.4 134.5v1.7l.3 .3M153.5 132.7l.1-.1a.54 .54 0 0 1 .8 .3l-.1 .7a.54 .54 0 0 1-.5 .2 .54 .54 0 0 1-.4-.3zM153.5 135.3l.1-.1a.54 .54 0 0 1 .8 .3l-.1 .8a.54 .54 0 0 1-.5 .2 .54 .54 0 0 1-.4-.4zM155 132.5h.8M155 135.1h.8M155.3 131.8v1.8l.1 .1 .4 .1M155.3 134.5v1.7l.1 .2 .4 .1M157.1 132.6l-.5-.1-.3 .3 .1 .3 .7 .2v.4h-.8M157.1 135.2l-.5-.1-.3 .3 .1 .3 .7 .2v.5h-.8M157.9 131.6a2.29 2.29 0 0 1 0 3M157.9 134.2a2.29 2.29 0 0 1 0 3M92 149.1l1-1 1 1-1 1z"/>
<path d="M92 148.1l2 2M92 152.3h2M92.1 145.2l1.9 1.8M92.2 154.8h1.5v1.5h-1.5zM92.4 145.5h1.3v1.3h-1.3zM92.7 142.9l1.3 1.2M92.7 143.5h1.3M92.9 140.3l1.1 1.1M93 151.3v2M93.3 142.9v1.2M94 142.9l-1.3 1.2M94 148.1l-2 2"/>
<path d="M94 140.3l-1.1 1.1M94 145.2l-1.9 1.8M130.3 145.6l.6-.6v2M130.3 147h1.2M133.9 140.6a.5 .5 0 0 1 .8 .1v1.1M133.9 145.9a.5 .5 0 0 1 .8 .1v1M133.9 148.9a.5 .5 0 0 1 .8 .1v1M133.9 152.1a.5 .5 0 0 1 .8 .1v1M133.9 155.3a.5 .5 0 0 1 .8 .1v1M133.9 145v2M133.9 148v2M133.9 151.2v2"/>
<path d="M133.9 154.4v2M134.1 142.6l.3-.2 .7 .1a.54 .54 0 0 1 .1 .8l-1.1 1.1h1.2M135.7 140.6a.54 .54 0 0 1 .5-.2 .54 .54 0 0 1 .4 .4l-.1 .8a.54 .54 0 0 1-.5 .2 .54 .54 0 0 1-.4-.4zM135.7 145.9a.54 .54 0 0 1 .5-.2 .54 .54 0 0 1 .4 .4v.6a.54 .54 0 0 1-.5 .4 .54 .54 0 0 1-.5-.4zM135.7 152.1a.54 .54 0 0 1 .5-.2 .54 .54 0 0 1 .4 .4v.6a.54 .54 0 0 1-.5 .4 .54 .54 0 0 1-.5-.4zM135.7 155.3a.54 .54 0 0 1 .5-.2 .54 .54 0 0 1 .4 .4l-.1 .8a.54 .54 0 0 1-.5 .2 .54 .54 0 0 1-.4-.4zM135.8 148.8a.54 .54 0 0 1 .8 .3v.6a.54 .54 0 0 1-.5 .4 .54 .54 0 0 1-.5-.4v-.6zM137.5 145v1.8l.3 .2M137.5 148v1.8l.3 .2M137.5 151.2v1.8l.3 .2M137.5 154.4v1.8l.3 .2M137.7 143.3a.5 .5 0 0 1 .8 0v1.1"/>
<path d="M137.7 142.4v2M138.4 141.1l1-.2-.1-.4-.6-.1-.3 .3 .1 1h.8M138.4 146.4l1-.2-.1-.4-.6-.1-.3 .3 .1 .9h.8M138.4 149.4l1-.2-.1-.4-.6-.1-.3 .3 .1 1h.8M138.4 152.6l1-.2-.1-.4-.6-.1-.3 .3 .1 1h.8M138.4 155.8l1-.2-.1-.4-.6-.1-.3 .3 .1 1h.8M139.5 143.3l.3-.2 .5 .2 .1 .7-.2 .3-.4 .1-.3-.2zM140.1 144.8a2.29 2.29 0 0 1 0 3M140.9 140.5l-.5-.1-.3 .3 .1 .3 .7 .2v.5h-.8M140.9 148.8l-.5-.1-.3 .3 .1 .3 .7 .2v.5h-.8M140.9 152l-.5-.1-.3 .3 .1 .3 .7 .2v.5h-.8M140.9 155.2l-.5-.1-.3 .3 .1 .3 .7 .2v.5h-.8"/>
<path d="M141.3 142.4v1.7l.3 .3M141.7 147.8a2.29 2.29 0 0 1 0 3M141.7 151a2.29 2.29 0 0 1 0 3M141.7 154.2a2.29 2.29 0 0 1 0 3M142.2 143.7l1-.2-.1-.3-.6-.1-.3 .2 .1 1h.8M144.7 143.2l-.5-.1-.2 .2 .1 .3 .6 .2v.5h-.7M145.5 142.1a2.29 2.29 0 0 1 0 3.1"/>
<circle cx="173.9" cy="51.3" r=".15"/>
<circle cx="173.9" cy="49.9" r=".15"/>
<circle cx="175.2" cy="51.3" r=".15"/>
<circle cx="175.2" cy="49.9" r=".15"/>
<circle cx="176.5" cy="51.3" r=".15"/>
<circle cx="176.5" cy="49.9" r=".15"/>
<circle cx="104.2" cy="77.1" r=".54"/>
<circle cx="104.2" cy="80.2" r=".54"/>
<circle cx="93.8" cy="130.3" r=".15"/>
<circle cx="93" cy="152.3" r="1"/>
<circle cx="93" cy="155.5" r="1"/>
<circle cx="93.4" cy="140.9" r=".54"/>
</g>
<g fill="none" stroke="#000" stroke-width=".27">
<path d="M137.1 82.6h2.6M138.4 81.3v2.7M187.2 82.6h2.6M188.5 81.3v2.7M140.7 105.9h2.7M142.1 104.6v2.7M187.2 105.9h2.6M188.5 104.6v2.7"/>
<circle cx="138.4" cy="82.6" r="1.33"/>
<circle cx="188.5" cy="82.6" r="1.33"/>
<circle cx="142.1" cy="105.9" r="1.33"/>
<circle cx="188.5" cy="105.9" r="1.33"/>
</g>
<g fill="none" stroke="#000" stroke-width=".39">
<path d="M103.4 10.1h2.8v2.8h-2.8zM192.4 10.1h2.7v2.8h-2.7zM98.8 113.6h2.8v2.8h-2.8zM195.4 113.6h2.8v2.8h-2.8z"/>
<circle cx="104.8" cy="11.5" r="1.93"/>
<circle cx="193.7" cy="11.5" r="1.93"/>
<circle cx="100.2" cy="115" r="1.93"/>
<circle cx="196.8" cy="115" r="1.93"/>
</g>
<use href="#words"/>
</svg>
